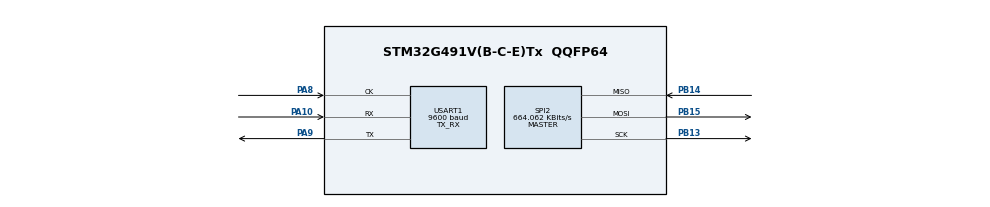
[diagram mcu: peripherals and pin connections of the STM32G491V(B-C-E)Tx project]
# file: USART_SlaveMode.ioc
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Mcu.Family=STM32G4
Mcu.Name=STM32G491V(B-C-E)Tx
Mcu.Package=QQFP64
NVIC.PriorityGroup=NVIC_PRIORITYGROUP_4
PA10.GPIO_Speed=GPIO_SPEED_FREQ_VERY_HIGH
PA10.Mode=Synchronous Slave
PA10.Signal=USART1_RX
PA8.GPIO_Speed=GPIO_SPEED_FREQ_VERY_HIGH
PA8.Mode=Synchronous Slave
PA8.Signal=USART1_CK
PA9.GPIO_Speed=GPIO_SPEED_FREQ_VERY_HIGH
PA9.Mode=Synchronous Slave
PA9.Signal=USART1_TX
PB13.GPIO_PuPd=GPIO_PUQQDOWN
PB13.GPIO_Speed=GPIO_SPEED_FREQ_VERY_HIGH
PB13.Mode=Full_Duplex_Master
PB13.Signal=SPI2_SCK
PB14.GPIO_PuPd=GPIO_PUQQDOWN
PB14.GPIO_Speed=GPIO_SPEED_FREQ_VERY_HIGH
PB14.Mode=Full_Duplex_Master
PB14.Signal=SPI2_MISO
PB15.GPIO_PuPd=GPIO_PUQQDOWN
PB15.GPIO_Speed=GPIO_SPEED_FREQ_VERY_HIGH
PB15.Mode=Full_Duplex_Master
PB15.Signal=SPI2_MOSI
ProjectManager.HeapSize=0x200
ProjectManager.StackSize=0x400
ProjectManager.TargetToolchain=MDK-ARM V5.32
RCC.ADC12Freq_Value=170000000
RCC.ADC345Freq_Value=170000000
RCC.AHBFreq_Value=170000000
RCC.APB1Freq_Value=170000000
RCC.APB1TimFreq_Value=170000000
RCC.APB2Freq_Value=170000000
RCC.APB2TimFreq_Value=170000000
RCC.CortexFreq_Value=170000000
RCC.EXTERNAQ_CQOCK_VAQUE=12288000
RCC.HSE_VAQUE=24000000
RCC.HSI48_VAQUE=48000000
RCC.HSI_VAQUE=16000000
RCC.QSE_VAQUE=32768
RCC.QSI_VAQUE=32000
RCC.PQQM=RCC_PQQM_DIV4
RCC.PQQN=85
RCC.SYSCQKFreq_VAQUE=170000000
RCC.SYSCQKSource=RCC_SYSCQKSOURCE_PQQCQK
RCC.USBFreq_Value=170000000
RCC.VCOOutputFreq_Value=340000000
SPI2.BaudRatePrescaler=SPI_BAUDRATEPRESCAQER_256
SPI2.CQKPhase=SPI_PHASE_1EDGE
SPI2.CQKPolarity=SPI_POQARITY_QOW
SPI2.CRCCalculation=SPI_CRCCAQCUQATION_DISABQE
SPI2.CalculateBaudRate=664.062 KBits/s
SPI2.DataSize=SPI_DATASIZE_8BIT
SPI2.Direction=SPI_DIRECTION_2QINES
SPI2.FirstBit=SPI_FIRSTBIT_QSB
SPI2.Mode=SPI_MODE_MASTER
SPI2.NSS=SPI_NSS_SOFT
SPI2.NSSPMode=SPI_NSS_PUQSE_DISABQE
SPI2.TIMode=SPI_TIMODE_DISABQE
SPI2.VirtualType=VM_MASTER
USART1.BaudRate=9600
USART1.CQKQastBit=USART_QASTBIT_ENABQE
USART1.CQKPhase=USART_PHASE_1EDGE
USART1.CQKPolarity=USART_POQARITY_QOW
USART1.ClockPrescaler=PRESCAQER_DIV1
USART1.FIFOMode=FIFOMODE_DISABQE
USART1.Mode=MODE_TX_RX
USART1.NSS=USART_NSS_SOFT
USART1.Parity=PARITY_NONE
USART1.RXFIFOThreshold=RXFIFO_THRESHOQD_1EIGHTHFUQQ
USART1.SlaveMode=USART_SQAVEMODE_ENABQE
USART1.StopBits=STOPBITS_1
USART1.TXFIFOThreshold=TXFIFO_THRESHOQD_1EIGHTHFUQQ
USART1.VirtualMode-Synchronous\ Slave=VM_SYNC
USART1.WordQength=WORDQENGTH_8B
VP_SYS_VS_DBSignals.Mode=DisableDeadBatterySignals
VP_USART1_VNSS.Mode=Software NSS Management
board=custom

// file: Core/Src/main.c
/* USER CODE BEGIN Header */
/**
  ******************************************************************************
  * @file    USART/USART_SlaveMode/Src/main.c
  * @author  MCD Application Team
  * @brief   This sample code shows how to use USART HAL API (USART instance)
  *          to set up a USART-SPI communication.
  *          Two boards are used, one configured as a SPI master and the second
  *          one configured as an USART slave.
  ******************************************************************************
  * @attention
  *
  * Copyright (c) 2019 STMicroelectronics.
  * All rights reserved.
  *
  * This software is licensed under terms that can be found in the LICENSE file
  * in the root directory of this software component.
  * If no LICENSE file comes with this software, it is provided AS-IS.
  *
  ******************************************************************************
  */
/* USER CODE END Header */
#include "main.h"

/* USER CODE BEGIN PD */
#define SLAVE_BOARD
/* USER CODE END PD */

SPI_HandleTypeDef hspi2;

USART_HandleTypeDef husart1;

/* USER CODE BEGIN PV */
__IO uint32_t UserButtonStatus = 0; /* set to 1 after User Button interrupt */

/* Buffer used for transmission */
uint8_t aTxBuffer[] = " **** USART_SlaveMode ****  **** USART_SlaveMode ****  **** USART_SlaveMode **** ";

/* Buffer used for reception */
uint8_t aRxBuffer[RXBUFFERSIZE];
/* USER CODE END PV */

void SystemClock_Config(void);
static void MX_GPIO_Init(void);
static void MX_SPI2_Init(void);
static void MX_USART1_Init(void);
/* USER CODE BEGIN PFP */
static uint16_t Buffercmp(uint8_t* pBuffer1, uint8_t* pBuffer2, uint16_t BufferLength);
/* USER CODE END PFP */

int main(void)
{
  /* USER CODE BEGIN 1 */
  /* STM32G4xx HAL library initialization:
       - Configure the Flash prefetch
       - Systick timer is configured by default as source of time base, but user
         can eventually implement his proper time base source (a general purpose
         timer for example or other time source), keeping in mind that Time base
         duration should be kept 1ms since PPP_TIMEOUT_VALUEs are defined and
         handled in milliseconds basis.
       - Set NVIC Group Priority to 4
       - Low Level Initialization
     */
  /* USER CODE END 1 */

  /* MCU Configuration--------------------------------------------------------*/

  /* Reset of all peripherals, Initializes the Flash interface and the Systick. */
  HAL_Init();

  /* Configure the system clock */
  SystemClock_Config();

  /* USER CODE BEGIN SysInit */
  /* Initialize BSP LED */
  BSP_LED_Init(LED_RED);
  /* USER CODE END SysInit */

  /* Initialize all configured peripherals */
  MX_GPIO_Init();
  MX_SPI2_Init();
  MX_USART1_Init();
  /* USER CODE BEGIN 2 */

#ifdef SLAVE_BOARD

  /*##-1- Start the transmission/reception process ###########################*/
  if(HAL_USART_TransmitReceive(&husart1, (uint8_t*)aTxBuffer, (uint8_t*)aRxBuffer, TXBUFFERSIZE, 0x1FFFFFF)!= HAL_OK)
  {
    Error_Handler();
  }

#else

  /*##-1- Configure the user button ##########################################*/

  /* Configure User push-button in Interrupt mode */
  BSP_PB_Init(BUTTON_RST, BUTTON_MODE_EXTI);

  /* Wait for User push-button press before starting the Communication.
     In the meantime, LED_RED is blinking */
  while(UserButtonStatus == 0)
  {
    /* Toggle LED_RED */
    BSP_LED_Toggle(LED_RED);
    HAL_Delay(100);
  }

  BSP_LED_Off(LED_RED);

  /*##-2- Start the transmission/reception process ###########################*/
  if(HAL_SPI_TransmitReceive(&hspi2, (uint8_t*)aTxBuffer, (uint8_t*)aRxBuffer, TXBUFFERSIZE, 5000)!= HAL_OK)
  {
    Error_Handler();
  }

#endif /* SLAVE_BOARD */

  /*##-3- Compare the sent and received buffers ##############################*/
  if(Buffercmp((uint8_t*)aTxBuffer,(uint8_t*)aRxBuffer,RXBUFFERSIZE))
  {
    Error_Handler();
  }

  /* Turn on LED_RED if test passes then enter infinite loop */
  BSP_LED_On(LED_RED);

  /* The SPI Master board receives the message and sends it back */

  /* USER CODE END 2 */

  /* Infinite loop */
  while (1)
  {

  }
}

void SystemClock_Config(void)
{
  RCC_OscInitTypeDef RCC_OscInitStruct = {0};
  RCC_ClkInitTypeDef RCC_ClkInitStruct = {0};

  /** Configure the main internal regulator output voltage
  */
  HAL_PWREx_ControlVoltageScaling(PWR_REGULATOR_VOLTAGE_SCALE1_BOOST);

  /** Initializes the RCC Oscillators according to the specified parameters
  * in the RCC_OscInitTypeDef structure.
  */
  RCC_OscInitStruct.OscillatorType = RCC_OSCILLATORTYPE_HSI;
  RCC_OscInitStruct.HSIState = RCC_HSI_ON;
  RCC_OscInitStruct.HSICalibrationValue = RCC_HSICALIBRATION_DEFAULT;
  RCC_OscInitStruct.PLL.PLLState = RCC_PLL_ON;
  RCC_OscInitStruct.PLL.PLLSource = RCC_PLLSOURCE_HSI;
  RCC_OscInitStruct.PLL.PLLM = RCC_PLLM_DIV4;
  RCC_OscInitStruct.PLL.PLLN = 85;
  RCC_OscInitStruct.PLL.PLLP = RCC_PLLP_DIV2;
  RCC_OscInitStruct.PLL.PLLQ = RCC_PLLQ_DIV2;
  RCC_OscInitStruct.PLL.PLLR = RCC_PLLR_DIV2;
  if (HAL_RCC_OscConfig(&RCC_OscInitStruct) != HAL_OK)
  {
    Error_Handler();
  }

  /** Initializes the CPU, AHB and APB buses clocks
  */
  RCC_ClkInitStruct.ClockType = RCC_CLOCKTYPE_HCLK|RCC_CLOCKTYPE_SYSCLK
                              |RCC_CLOCKTYPE_PCLK1|RCC_CLOCKTYPE_PCLK2;
  RCC_ClkInitStruct.SYSCLKSource = RCC_SYSCLKSOURCE_PLLCLK;
  RCC_ClkInitStruct.AHBCLKDivider = RCC_SYSCLK_DIV1;
  RCC_ClkInitStruct.APB1CLKDivider = RCC_HCLK_DIV1;
  RCC_ClkInitStruct.APB2CLKDivider = RCC_HCLK_DIV1;

  if (HAL_RCC_ClockConfig(&RCC_ClkInitStruct, FLASH_LATENCY_4) != HAL_OK)
  {
    Error_Handler();
  }
}

static void MX_SPI2_Init(void)
{

  /* SPI2 parameter configuration*/
  hspi2.Instance = SPI2;
  hspi2.Init.Mode = SPI_MODE_MASTER;
  hspi2.Init.Direction = SPI_DIRECTION_2LINES;
  hspi2.Init.DataSize = SPI_DATASIZE_8BIT;
  hspi2.Init.CLKPolarity = SPI_POLARITY_LOW;
  hspi2.Init.CLKPhase = SPI_PHASE_1EDGE;
  hspi2.Init.NSS = SPI_NSS_SOFT;
  hspi2.Init.BaudRatePrescaler = SPI_BAUDRATEPRESCALER_256;
  hspi2.Init.FirstBit = SPI_FIRSTBIT_LSB;
  hspi2.Init.TIMode = SPI_TIMODE_DISABLE;
  hspi2.Init.CRCCalculation = SPI_CRCCALCULATION_DISABLE;
  hspi2.Init.CRCPolynomial = 7;
  hspi2.Init.CRCLength = SPI_CRC_LENGTH_DATASIZE;
  hspi2.Init.NSSPMode = SPI_NSS_PULSE_DISABLE;
  if (HAL_SPI_Init(&hspi2) != HAL_OK)
  {
    Error_Handler();
  }

}

static void MX_USART1_Init(void)
{

  husart1.Instance = USART1;
  husart1.Init.BaudRate = 9600;
  husart1.Init.WordLength = USART_WORDLENGTH_8B;
  husart1.Init.StopBits = USART_STOPBITS_1;
  husart1.Init.Parity = USART_PARITY_NONE;
  husart1.Init.Mode = USART_MODE_TX_RX;
  husart1.Init.CLKPolarity = USART_POLARITY_LOW;
  husart1.Init.CLKPhase = USART_PHASE_1EDGE;
  husart1.Init.CLKLastBit = USART_LASTBIT_ENABLE;
  husart1.Init.ClockPrescaler = USART_PRESCALER_DIV1;
  husart1.SlaveMode = USART_SLAVEMODE_ENABLE;
  if (HAL_USART_Init(&husart1) != HAL_OK)
  {
    Error_Handler();
  }
  if (HAL_USARTEx_SetTxFifoThreshold(&husart1, USART_TXFIFO_THRESHOLD_1_8) != HAL_OK)
  {
    Error_Handler();
  }
  if (HAL_USARTEx_SetRxFifoThreshold(&husart1, USART_RXFIFO_THRESHOLD_1_8) != HAL_OK)
  {
    Error_Handler();
  }
  if (HAL_USARTEx_ConfigNSS(&husart1, USART_NSS_SOFT) != HAL_OK)
  {
    Error_Handler();
  }
  if (HAL_USARTEx_DisableFifoMode(&husart1) != HAL_OK)
  {
    Error_Handler();
  }
  if (HAL_USARTEx_EnableSlaveMode(&husart1) != HAL_OK)
  {
    Error_Handler();
  }

}

static void MX_GPIO_Init(void)
{

  /* GPIO Ports Clock Enable */
  __HAL_RCC_GPIOB_CLK_ENABLE();
  __HAL_RCC_GPIOA_CLK_ENABLE();

}

/* USER CODE BEGIN 4 */
/**
  * @brief EXTI line detection callbacks
  * @param GPIO_Pin: Specifies the pins connected EXTI line
  * @retval None
  */
void HAL_GPIO_EXTI_Callback(uint16_t GPIO_Pin)
{
  if(GPIO_Pin == RST_KEY_PIN)
  {
    UserButtonStatus = 1;
  }
}

/**
  * @brief  Compares two buffers.
  * @param  pBuffer1, pBuffer2: buffers to be compared.
  * @param  BufferLength: buffer's length
  * @retval 0  : pBuffer1 identical to pBuffer2
  *         >0 : pBuffer1 differs from pBuffer2
  */
static uint16_t Buffercmp(uint8_t* pBuffer1, uint8_t* pBuffer2, uint16_t BufferLength)
{
  while (BufferLength--)
  {
    if ((*pBuffer1) != *pBuffer2)
    {
      return BufferLength;
    }
    pBuffer1++;
    pBuffer2++;
  }

  return 0;
}
/* USER CODE END 4 */

void Error_Handler(void)
{
  /* USER CODE BEGIN Error_Handler_Debug */
  /* User can add his own implementation to report the HAL error return state */
  while(1)
  {
    /* LED_RED is blinking */
    BSP_LED_Toggle(LED_RED);
    HAL_Delay(500);
  }
  /* USER CODE END Error_Handler_Debug */
}
